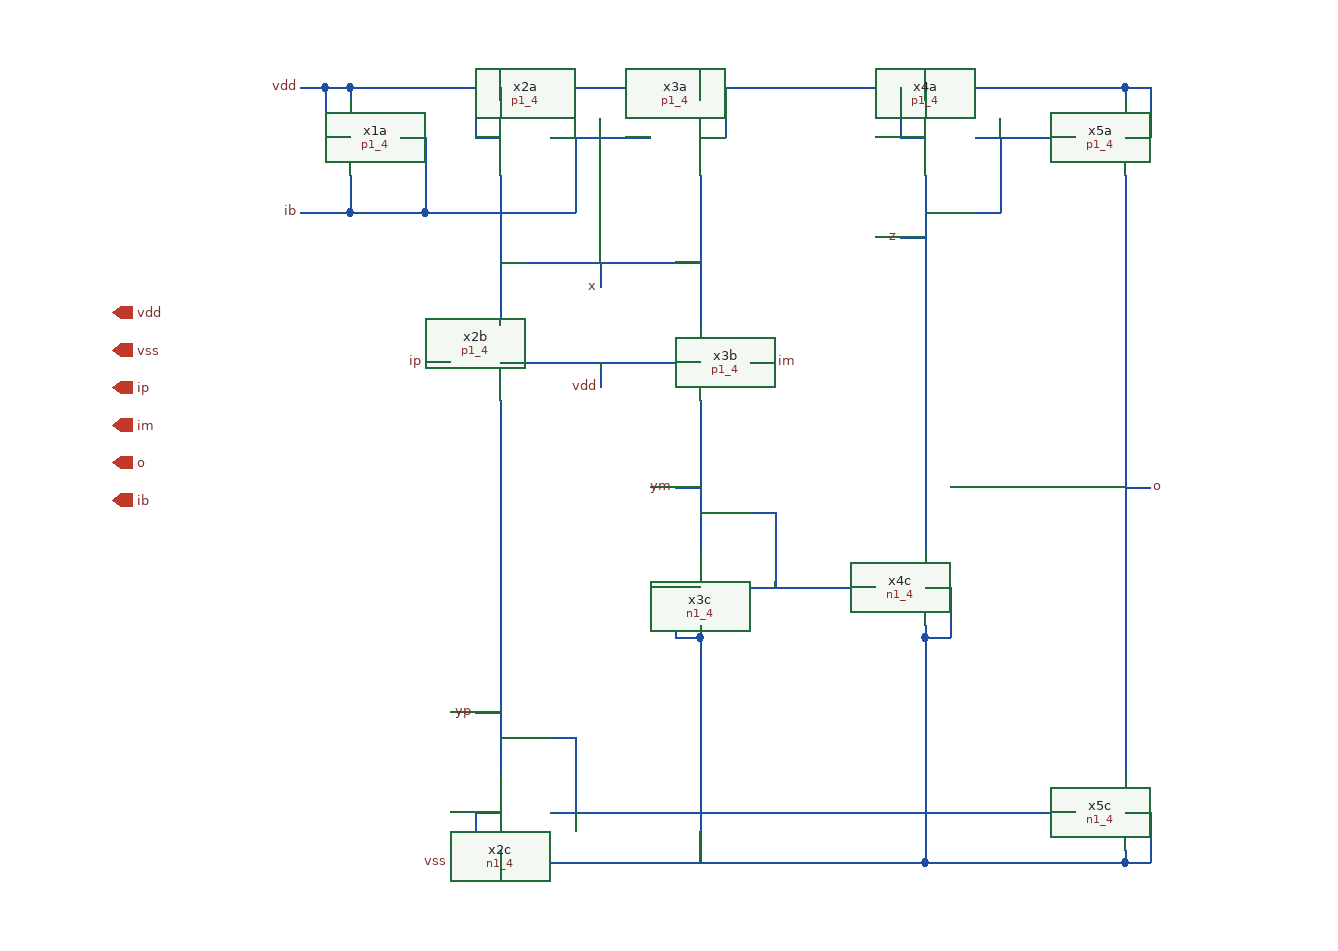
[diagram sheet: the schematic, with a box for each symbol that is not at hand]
v {xschem version=2.9.9 file_version=1.2 }
G {}
K {}
V {}
S {}
E {}
N 520 -650 520 -530 { lab=x}
N 360 -650 360 -530 { lab=x}
N 360 -580 520 -580 { lab=x}
N 420 -200 420 -140 { lab=yp}
N 360 -200 420 -200 { lab=yp}
N 360 -110 360 -100 { lab=vss}
N 340 -100 360 -100 { lab=vss}
N 340 -140 340 -100 { lab=vss}
N 340 -140 360 -140 { lab=vss}
N 360 -500 520 -500 { lab=vdd}
N 400 -680 480 -680 { lab=ib}
N 280 -680 300 -680 { lab=ib}
N 300 -680 300 -620 { lab=ib}
N 240 -620 300 -620 { lab=ib}
N 240 -650 240 -620 { lab=ib}
N 220 -680 240 -680 { lab=vdd}
N 220 -720 220 -680 { lab=vdd}
N 240 -720 520 -720 { lab=vdd}
N 520 -720 520 -710 { lab=vdd}
N 360 -720 360 -710 { lab=vdd}
N 240 -720 240 -710 { lab=vdd}
N 220 -720 240 -720 { lab=vdd}
N 300 -620 420 -620 { lab=ib}
N 420 -680 420 -620 { lab=ib}
N 340 -720 340 -680 { lab=vdd}
N 340 -680 360 -680 { lab=vdd}
N 520 -680 540 -680 { lab=vdd}
N 540 -720 540 -680 { lab=vdd}
N 440 -580 440 -560 { lab=x}
N 200 -720 220 -720 { lab=vdd}
N 200 -620 240 -620 { lab=ib}
N 340 -220 360 -220 { lab=yp}
N 320 -100 340 -100 { lab=vss}
N 440 -500 440 -480 { lab=vdd}
N 560 -500 580 -500 { lab=im}
N 300 -500 320 -500 { lab=ip}
N 700 -290 700 -280 { lab=vss}
N 700 -320 720 -320 { lab=vss}
N 720 -320 720 -280 { lab=vss}
N 860 -110 860 -100 { lab=vss}
N 860 -140 880 -140 { lab=vss}
N 880 -140 880 -100 { lab=vss}
N 860 -100 880 -100 { lab=vss}
N 860 -650 860 -170 { lab=z}
N 740 -680 820 -680 { lab=z}
N 760 -680 760 -620 { lab=z}
N 700 -620 760 -620 { lab=z}
N 360 -100 700 -100 { lab=vss}
N 700 -100 860 -100 { lab=vss}
N 520 -290 520 -280 { lab=vss}
N 500 -320 520 -320 { lab=vss}
N 500 -320 500 -280 { lab=vss}
N 560 -320 660 -320 { lab=ym}
N 520 -380 580 -380 { lab=ym}
N 580 -380 580 -320 { lab=ym}
N 520 -470 520 -350 { lab=ym}
N 700 -650 700 -350 { lab=z}
N 360 -470 360 -170 { lab=yp}
N 400 -140 820 -140 { lab=yp}
N 700 -280 700 -100 { lab=vss}
N 520 -280 520 -100 { lab=vss}
N 500 -280 520 -280 { lab=vss}
N 700 -280 720 -280 { lab=vss}
N 500 -400 520 -400 { lab=ym}
N 680 -600 700 -600 { lab=z}
N 520 -720 860 -720 { lab=vdd}
N 860 -720 860 -710 { lab=vdd}
N 700 -720 700 -710 { lab=vdd}
N 680 -680 700 -680 { lab=vdd}
N 680 -720 680 -680 { lab=vdd}
N 860 -680 880 -680 { lab=vdd}
N 880 -720 880 -680 { lab=vdd}
N 860 -720 880 -720 { lab=vdd}
N 860 -400 880 -400 { lab=z}
C {devices/lab_pin.sym} 580 -500 2 0 {name=l16 sig_type=std_logic lab=im}
C {devices/title.sym} 160 -40 0 0 {name=l6 author="Luis Henrique Rodovalho"}
C {devices/iopin.sym} 50 -540 2 1 {name=p1 lab=vdd}
C {devices/iopin.sym} 50 -510 2 1 {name=p2 lab=vss}
C {devices/iopin.sym} 50 -480 2 1 {name=p3 lab=ip}
C {devices/iopin.sym} 50 -450 2 1 {name=p4 lab=im}
C {devices/iopin.sym} 50 -420 2 1 {name=p5 lab=o}
C {devices/iopin.sym} 50 -390 2 1 {name=p6 lab=ib}
C {devices/lab_pin.sym} 200 -720 2 1 {name=l1 sig_type=std_logic lab=vdd}
C {devices/lab_pin.sym} 300 -500 2 1 {name=l5 sig_type=std_logic lab=ip
}
C {p1_4.sym} 260 -680 0 1 {name=x1a}
C {p1_4.sym} 380 -680 0 1 {name=x2a}
C {p1_4.sym} 500 -680 0 0 {name=x3a}
C {n1_4.sym} 540 -320 0 1 {name=x3c}
C {n1_4.sym} 380 -140 0 1 {name=x2c}
C {p1_4.sym} 340 -500 0 0 {name=x2b}
C {p1_4.sym} 540 -500 0 1 {name=x3b}
C {devices/lab_pin.sym} 440 -560 0 0 {name=l2 sig_type=std_logic lab=x}
C {devices/lab_pin.sym} 200 -620 2 1 {name=l4 sig_type=std_logic lab=ib}
C {devices/lab_pin.sym} 340 -220 2 1 {name=l7 sig_type=std_logic lab=yp
}
C {devices/lab_pin.sym} 320 -100 2 1 {name=l3 sig_type=std_logic lab=vss}
C {devices/lab_pin.sym} 440 -480 0 0 {name=l9 sig_type=std_logic lab=vdd}
C {p1_4.sym} 720 -680 0 1 {name=x4a}
C {n1_4.sym} 680 -320 0 0 {name=x4c}
C {p1_4.sym} 840 -680 0 0 {name=x5a}
C {n1_4.sym} 840 -140 0 0 {name=x5c}
C {devices/lab_pin.sym} 500 -400 2 1 {name=l8 sig_type=std_logic lab=ym
}
C {devices/lab_pin.sym} 680 -600 2 1 {name=l10 sig_type=std_logic lab=z
}
C {devices/lab_pin.sym} 880 -400 2 0 {name=l11 sig_type=std_logic lab=o
}
